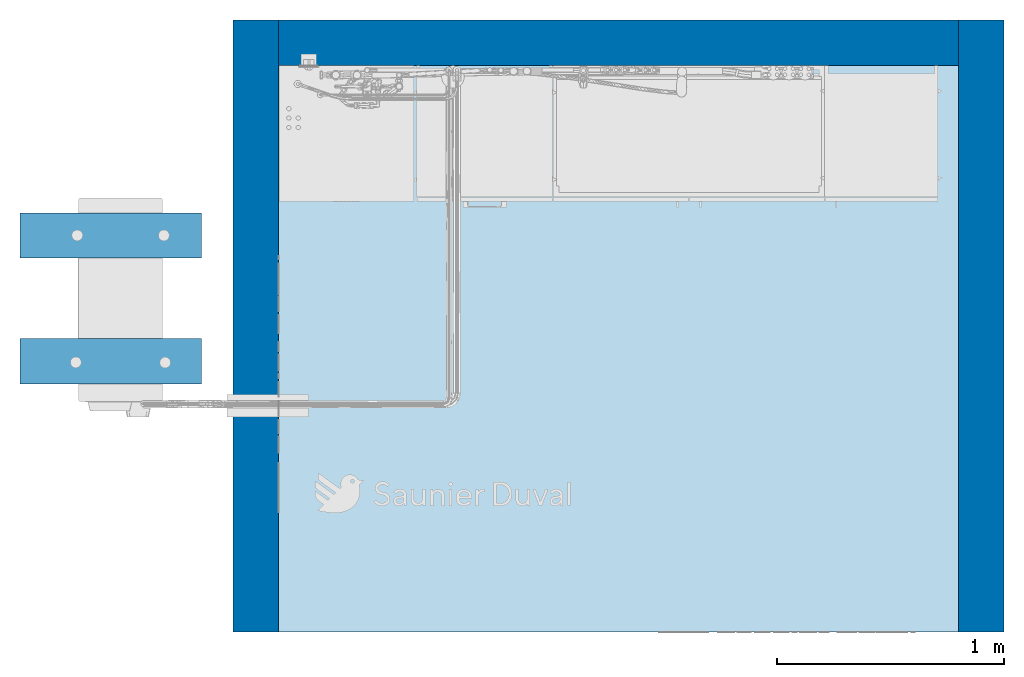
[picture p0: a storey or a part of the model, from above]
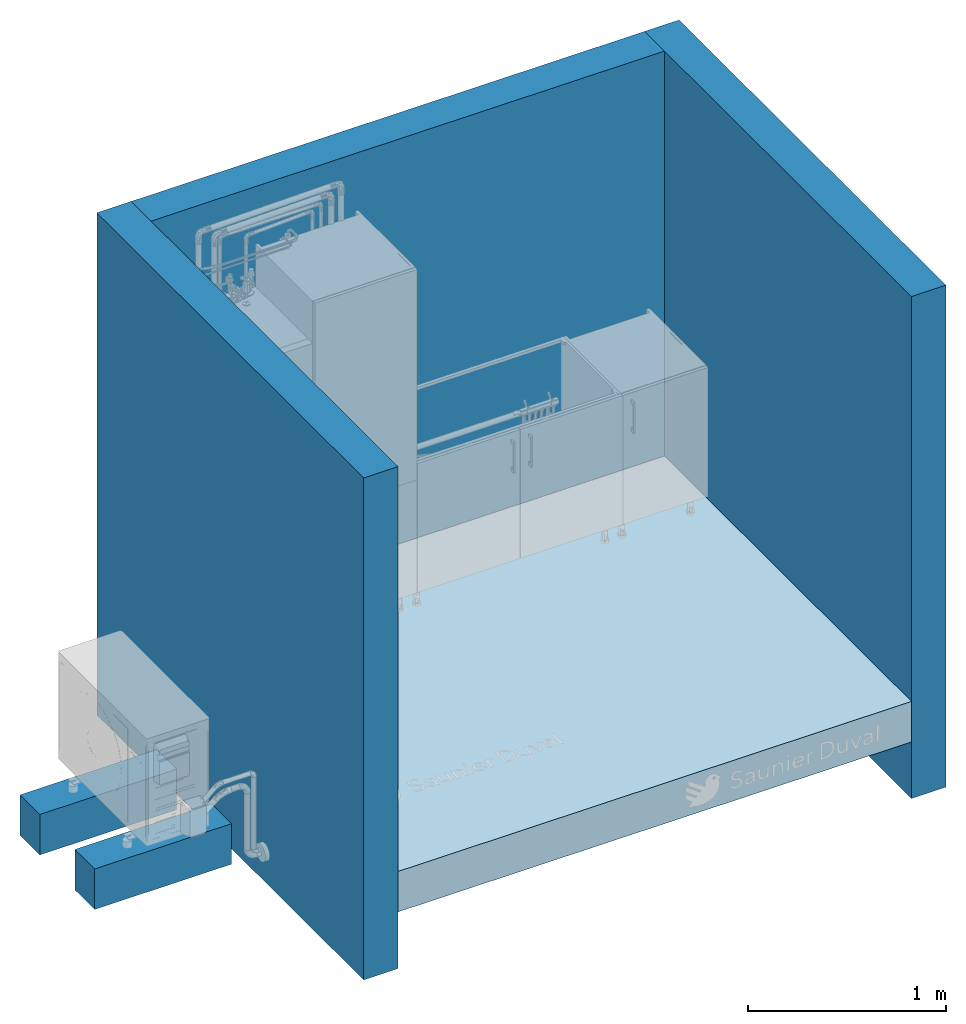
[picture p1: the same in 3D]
Properties of the parts of a building model (IFC2X3)

# File
Description: ViewDefinition [CoordinationView_V2.0], RevitIdentifiers [VersionGUID: d87a4e5c-1366-4f79-aa34-87cf10b37c27, NumberOfSaves: 158], CoordinateReference [CoordinateBase: Coordonnées partagées]
File name: 0001
Time: 2024-07-11T15:00:22+01:00
Written by: ODA SDAI 24.6
Made in: Autodesk Revit 24.2.0.63 (FRA) - IFC 24.2.0.63

# IfcProject, 0001
LongName: Salle de formation PAC SD; Phase: Etat du projet

# IfcSite, Default
RefLatitude: 48, 52, 0, 117187; RefLongitude: 2, 19, 59, 880409; RefElevation: 0 m

# IfcBuilding
Pset_BuildingCommon - NumberOfStoreys: 1

# IfcBuildingStorey: Niveau:Ligne du Niveau (2)
Name | LongName | Elevation (m)
Niveau 0 | Niveau 0 | -1.94916e-14
Niveau 1 | Niveau 1 | 2.5

# IfcBuildingElementProxy: Legrand Boite encastrement batibox 1 poste1:1 poste, Legrand Boite encastrement batibox 1 poste1:1 poste:1152296
In: Niveau 0
Type - Material: Plastique orange
Type - Pset_ManufacturerTypeInformation - Manufacturer: Legrand
Pset_BuildingElementProxyCommon - Reference: 1 poste; sets with these values: 2

# IfcBuildingElementProxy: Legrand Sorties de câbles:Prise courant, Legrand Sorties de câbles:Prise courant:1152295
In: Niveau 0
Type - Material: Plastique, blanc opaque, Plastique, noir opaque
Type - Pset_ManufacturerTypeInformation - Manufacturer: Legrand
Pset_BuildingElementProxyCommon - Reference: Prise courant; sets with these values: 2

# IfcBuildingElementProxy: Legrand plaque2:1 poste, Legrand plaque2:1 poste:1152297
In: Niveau 0
Type - Material: Plastique, blanc opaque
Type - Pset_ManufacturerTypeInformation - Manufacturer: Legrand
Pset_BuildingElementProxyCommon - Reference: 1 poste; sets with these values: 2

# IfcBuildingElementProxy: Legrand support universel-20181:1 poste, Legrand support universel-20181:1 poste:1152298
In: Niveau 0
Type - Material: Plastique, noir opaque
Type - Pset_ManufacturerTypeInformation - Manufacturer: Legrand
Pset_BuildingElementProxyCommon - Reference: 1 poste; sets with these values: 2

# IfcBuildingElementProxy: Logo_Geometry_SD_3Dx10-:Mur_horizontal (2)
In: Niveau 0
Type - Material: Color RGB 251-026-031, Color RGB 10-10-10
Pset_BuildingElementProxyCommon - Reference: Mur_horizontal; sets with these values: 2
Name (Logo_Geometry_SD_3Dx10-:Mur_horizontal:...)
1152291
1152294

# IfcBuildingElementProxy: Logo_Geometry_SD_3Dx10-:Sol, Logo_Geometry_SD_3Dx10-:Sol:1152293
In: Niveau 0
Type - Material: Color RGB 251-026-031, Color RGB 10-10-10
Pset_BuildingElementProxyCommon - Reference: Sol; sets with these values: 2

# IfcBuildingElementProxy: Pied antivibratile ep 40:Pied antivibratile ep 40 (4)
In: Niveau 0
Type - Material: Valeur par défaut Nouveau Matériau
Pset_BuildingElementProxyCommon - Reference: Pied antivibratile ep 40; sets with these values: 2
Name (Pied antivibratile ep 40:Pied antivibratile ep 40:...)
1152043
1152044
1152045
1152046

# IfcBuildingElementProxy: R580F:R580 3/4" x 1/2", R580F:R580 3/4" x 1/2":1152158
In: Niveau 0
Type - Material: Color RGB 169-131-7, Matériau du rendu 255-0-0
Material: <Unnamed>, Color RGB 169-131-7, Matériau du rendu 255-0-0; Group: Chauffage retour 2; Chauffage aller 1; Alimentation hydraulique 46; Alimentation hydraulique 45; Alimentation hydraulique 44; Alimentation hydraulique 43; Alimentation hydraulique 42; Alimentation hydraulique 41; Retour hydraulique 25; Retour hydraulique 24; Retour hydraulique 23; Retour hydraulique 22; Retour hydraulique 21; Retour hydraulique 20
Pset_BuildingElementProxyCommon - Reference: R580 3/4" x 1/2"; sets with these values: 2

# IfcCovering: Isolation des canalisations:Par défaut (24)
In: Niveau 0
Type - PredefinedType: INSULATION
Material: Matériau du rendu 255-255-255
Pset_CoveringCommon - Reference: Par défaut; sets with these values: 2
Name (Isolation des canalisations:Par défaut:...)
1152861
1152862
1152863
1152864
1152865
1152866
1152867
1152868
1152869
1152870
1152871
1152874
1152907
1152908
1152909
1152911
1152912
1152913
1152914
1152915
1152916
1152917
1152918
1219209

# IfcDistributionPort (264)
Description: Flow
Name | FlowDirection | Group
Port_530808_1 | SOURCEANDSINK | Alimentation hydraulique 3
Port_530808_2 | SOURCEANDSINK | Alimentation hydraulique 3
InPort_1152054_1 | SINK
InPort_1152054_2 | SINK
OutPort_1152054_3 | SOURCE | Sanitaire 20
Port_1152055_0 | SOURCEANDSINK | Sanitaire 21
Port_1152055_1 | SOURCEANDSINK | Sanitaire 21
InPort_1152065_4 | SINK | Retour hydraulique 10
OutPort_1152066_0 | SOURCE | Retour hydraulique 10
InPort_1152074_1 | SINK | Alimentation hydraulique 14
OutPort_1152065_5 | SOURCE | Alimentation hydraulique 14
Port_1152065_6 | SOURCEANDSINK
InPort_1152066_1 | SINK | Retour hydraulique 10
OutPort_1152068_1 | SOURCE | Retour hydraulique 10
InPort_1152068_2 | SINK | Retour hydraulique 10
OutPort_1152070_0 | SOURCE | Retour hydraulique 10
InPort_1152070_1 | SINK | Retour hydraulique 10
OutPort_1152220_1 | SOURCE | Retour hydraulique 10
InPort_1152236_1 | SINK | Alimentation hydraulique 14
OutPort_1152072_0 | SOURCE | Alimentation hydraulique 14
InPort_1152072_1 | SINK | Alimentation hydraulique 14
OutPort_1152076_1 | SOURCE | Alimentation hydraulique 14
InPort_1152076_2 | SINK | Alimentation hydraulique 14
OutPort_1152074_0 | SOURCE | Alimentation hydraulique 14
Port_1152086_0 | SOURCEANDSINK | Eau Froide Sanitaire 9
Port_1213014_1 | SOURCEANDSINK | Eau Froide Sanitaire 9
Port_1152086_1 | SOURCEANDSINK | Eau Froide Sanitaire 9
Port_1204610_1 | SOURCEANDSINK | Eau Froide Sanitaire 9
OutPort_1152098_0 | SOURCE | Chauffage retour 2
InPort_1152098_1 | SINK | Chauffage retour 2
OutPort_1218942_1 | SOURCE | Chauffage retour 2
OutPort_1152112_2 | SOURCE
InPort_1152112_5 | SINK | Eau Froide Sanitaire 9
OutPort_1152121_2 | SOURCE | Eau Froide Sanitaire 9
InPort_1152125_0 | SINK | Eau Froide Sanitaire 20
OutPort_1152112_6 | SOURCE | Eau Froide Sanitaire 20
InPort_1152123_0 | SINK | Eau Froide Sanitaire 19
OutPort_1152112_7 | SOURCE | Eau Froide Sanitaire 19
InPort_1152127_0 | SINK | Eau Froide Sanitaire 21
OutPort_1152112_8 | SOURCE | Eau Froide Sanitaire 21
InPort_1152119_0 | SINK | Eau Froide Sanitaire 9
OutPort_1205700_3 | SOURCE | Eau Froide Sanitaire 9
InPort_1152121_1 | SINK | Eau Froide Sanitaire 9
OutPort_1152119_1 | SOURCE | Eau Froide Sanitaire 9
OutPort_1152123_1 | SOURCE | Eau Froide Sanitaire 19
OutPort_1152125_1 | SOURCE | Eau Froide Sanitaire 20
OutPort_1152127_1 | SOURCE | Eau Froide Sanitaire 21
OutPort_1152129_2 | SOURCE
InPort_1152129_5 | SINK | Eau Chaude Sanitaire 9
OutPort_1152154_1 | SOURCE | Eau Chaude Sanitaire 9
OutPort_1152129_6 | SOURCE
InPort_1152136_0 | SINK | Eau Chaude Sanitaire 10
OutPort_1152129_7 | SOURCE | Eau Chaude Sanitaire 10
InPort_1152138_0 | SINK | Eau Chaude Sanitaire 11
OutPort_1152129_8 | SOURCE | Eau Chaude Sanitaire 11
OutPort_1152136_1 | SOURCE | Eau Chaude Sanitaire 10
OutPort_1152138_1 | SOURCE | Eau Chaude Sanitaire 11
InPort_1152144_1 | SINK | Eau Froide Sanitaire 9
OutPort_1152142_0 | SOURCE | Eau Froide Sanitaire 9
InPort_1152142_1 | SINK | Eau Froide Sanitaire 9
InPort_1152145_1 | SINK | Eau Froide Sanitaire 9
OutPort_1152144_2 | SOURCE | Eau Froide Sanitaire 9
InPort_1152147_1 | SINK | Eau Froide Sanitaire 9
OutPort_1152145_0 | SOURCE | Eau Froide Sanitaire 9
InPort_1205681_1 | SINK | Eau Froide Sanitaire 9
OutPort_1152147_2 | SOURCE | Eau Froide Sanitaire 9
InPort_1152154_2 | SINK | Eau Chaude Sanitaire 9
OutPort_1152152_0 | SOURCE | Eau Chaude Sanitaire 9
InPort_1152152_1 | SINK | Eau Chaude Sanitaire 9
OutPort_1152156_2 | SOURCE | Eau Chaude Sanitaire 9
InPort_1152156_1 | SINK | Eau Chaude Sanitaire 9
OutPort_1212866_0 | SOURCE | Eau Chaude Sanitaire 9
InPort_1152158_1 | SINK | Chauffage aller 1
OutPort_1217464_2 | SOURCE | Chauffage aller 1
InPort_1213780_1 | SINK | Chauffage retour 2
OutPort_1152158_2 | SOURCE | Chauffage retour 2
InPort_1152199_0 | SINK | Alimentation hydraulique 46
OutPort_1152158_3 | SOURCE | Alimentation hydraulique 46
InPort_1152197_0 | SINK | Alimentation hydraulique 45
OutPort_1152158_4 | SOURCE | Alimentation hydraulique 45
InPort_1152195_0 | SINK | Alimentation hydraulique 44
OutPort_1152158_5 | SOURCE | Alimentation hydraulique 44
InPort_1152193_0 | SINK | Alimentation hydraulique 43
OutPort_1152158_6 | SOURCE | Alimentation hydraulique 43
InPort_1152191_0 | SINK | Alimentation hydraulique 42
OutPort_1152158_7 | SOURCE | Alimentation hydraulique 42
InPort_1152189_0 | SINK | Alimentation hydraulique 41
OutPort_1152158_8 | SOURCE | Alimentation hydraulique 41
InPort_1152158_9 | SINK | Retour hydraulique 25
OutPort_1152187_0 | SOURCE | Retour hydraulique 25
InPort_1152158_10 | SINK | Retour hydraulique 24
OutPort_1152185_0 | SOURCE | Retour hydraulique 24
InPort_1152158_11 | SINK | Retour hydraulique 23
OutPort_1152183_0 | SOURCE | Retour hydraulique 23
InPort_1152158_12 | SINK | Retour hydraulique 22
OutPort_1152181_0 | SOURCE | Retour hydraulique 22
InPort_1152158_13 | SINK | Retour hydraulique 21
OutPort_1152179_0 | SOURCE | Retour hydraulique 21
InPort_1152158_14 | SINK | Retour hydraulique 20
OutPort_1152177_0 | SOURCE | Retour hydraulique 20
InPort_1218810_1 | SINK | Chauffage retour 2
OutPort_1152161_0 | SOURCE | Chauffage retour 2
InPort_1152161_1 | SINK | Chauffage retour 2
OutPort_1214416_2 | SOURCE | Chauffage retour 2
InPort_1152177_1 | SINK | Retour hydraulique 20
InPort_1152179_1 | SINK | Retour hydraulique 21
InPort_1152181_1 | SINK | Retour hydraulique 22
InPort_1152183_1 | SINK | Retour hydraulique 23
InPort_1152185_1 | SINK | Retour hydraulique 24
InPort_1152187_1 | SINK | Retour hydraulique 25
OutPort_1152189_1 | SOURCE | Alimentation hydraulique 41
OutPort_1152191_1 | SOURCE | Alimentation hydraulique 42
OutPort_1152193_1 | SOURCE | Alimentation hydraulique 43
OutPort_1152195_1 | SOURCE | Alimentation hydraulique 44
OutPort_1152197_1 | SOURCE | Alimentation hydraulique 45
OutPort_1152199_1 | SOURCE | Alimentation hydraulique 46
Port_1152201_0 | SOURCEANDSINK | Alimentation hydraulique 54
Port_1152201_1 | SOURCEANDSINK | Alimentation hydraulique 54
InPort_1152210_0 | SINK | Alimentation hydraulique 14
OutPort_1152836_2 | SOURCE | Alimentation hydraulique 14
InPort_1219448_1 | SINK | Alimentation hydraulique 14
OutPort_1152210_1 | SOURCE | Alimentation hydraulique 14
InPort_1152214_0 | SINK | Alimentation hydraulique 55
OutPort_1152216_2 | SOURCE | Alimentation hydraulique 55
InPort_1152224_2 | SINK | Alimentation hydraulique 55
OutPort_1152214_1 | SOURCE | Alimentation hydraulique 55
InPort_1152216_1 | SINK | Alimentation hydraulique 55
OutPort_1219199_0 | SOURCE | Alimentation hydraulique 55
InPort_1152220_2 | SINK | Retour hydraulique 10
OutPort_1152218_0 | SOURCE | Retour hydraulique 10
InPort_1152218_1 | SINK | Alimentation hydraulique 55
OutPort_1152226_1 | SOURCE | Alimentation hydraulique 55
InPort_1152222_0 | SINK | Alimentation hydraulique 55
OutPort_1152224_1 | SOURCE | Alimentation hydraulique 55
InPort_1152226_2 | SINK | Alimentation hydraulique 55
OutPort_1152222_1 | SOURCE | Alimentation hydraulique 55
InPort_1152836_1 | SINK | Alimentation hydraulique 14
OutPort_1152228_0 | SOURCE | Alimentation hydraulique 14
InPort_1152228_1 | SINK | Alimentation hydraulique 14
OutPort_1152240_2 | SOURCE | Alimentation hydraulique 14
InPort_1152232_0 | SINK | Alimentation hydraulique 14
OutPort_1152238_2 | SOURCE | Alimentation hydraulique 14
InPort_1152240_1 | SINK | Alimentation hydraulique 14
OutPort_1152232_1 | SOURCE | Alimentation hydraulique 14
InPort_1152234_0 | SINK | Alimentation hydraulique 14
OutPort_1152236_2 | SOURCE | Alimentation hydraulique 14
InPort_1152238_1 | SINK | Alimentation hydraulique 14
OutPort_1152234_1 | SOURCE | Alimentation hydraulique 14
Port_1152242_0 | SOURCEANDSINK | Alimentation hydraulique 57
Port_1152242_1 | SOURCEANDSINK | Alimentation hydraulique 57
Port_1152244_0 | SOURCEANDSINK | Alimentation hydraulique 58
Port_1152244_1 | SOURCEANDSINK | Alimentation hydraulique 58
Port_1152246_0 | SOURCEANDSINK | Alimentation hydraulique 59
Port_1152246_1 | SOURCEANDSINK | Alimentation hydraulique 59
Port_1152250_0 | SOURCEANDSINK | Alimentation hydraulique 61
Port_1152250_1 | SOURCEANDSINK | Alimentation hydraulique 61
Port_1152252_0 | SOURCEANDSINK | Alimentation hydraulique 62
Port_1152252_1 | SOURCEANDSINK | Alimentation hydraulique 62
Port_1152254_0 | SOURCEANDSINK | Alimentation hydraulique 63
Port_1152254_1 | SOURCEANDSINK | Alimentation hydraulique 63
Port_1152256_0 | SOURCEANDSINK | Alimentation hydraulique 64
Port_1152256_1 | SOURCEANDSINK | Alimentation hydraulique 64
Port_1152258_0 | SOURCEANDSINK | Alimentation hydraulique 65
Port_1152258_1 | SOURCEANDSINK | Alimentation hydraulique 65
Port_1152260_0 | SOURCEANDSINK | Alimentation hydraulique 66
Port_1152260_1 | SOURCEANDSINK | Alimentation hydraulique 66
InPort_1152288_10 | SINK
OutPort_1152288_11 | SOURCE
OutPort_1152288_16 | SOURCE
InPort_1385587_1 | SINK | Chauffage aller 1
OutPort_1152288_17 | SOURCE | Chauffage aller 1
InPort_1152288_18 | SINK | Chauffage retour 2
OutPort_1152288_19 | SOURCE
InPort_1152288_20 | SINK
OutPort_1152288_21 | SOURCE
InPort_1152288_22 | SINK
InPort_1152288_23 | SINK
OutPort_1152288_24 | SOURCE
OutPort_1152288_25 | SOURCE
Port_1152288_26 | SOURCEANDSINK
InPort_1219095_1 | SINK | Alimentation hydraulique 55
OutPort_1152583_0 | SOURCE | Alimentation hydraulique 55
InPort_1152583_1 | SINK | Alimentation hydraulique 55
OutPort_1152782_0 | SOURCE | Sanitaire 23
InPort_1152782_1 | SINK | Sanitaire 23
OutPort_1219401_1 | SOURCE | Sanitaire 23
Port_1204610_2 | SOURCEANDSINK | Eau Froide Sanitaire 9
Port_1205701_0 | SOURCEANDSINK | Eau Froide Sanitaire 9
InPort_1205700_2 | SINK | Eau Froide Sanitaire 9
OutPort_1205681_0 | SOURCE | Eau Froide Sanitaire 9
Port_1205700_1 | SOURCEANDSINK | Eau Froide Sanitaire 9
Port_1205701_1 | SOURCEANDSINK | Eau Froide Sanitaire 9
Port_1212275_0 | SOURCEANDSINK | Eau Froide Sanitaire 9
Port_1212275_1 | SOURCEANDSINK | Eau Froide Sanitaire 9
Port_1213012_1 | SOURCEANDSINK | Eau Froide Sanitaire 9
Port_1212283_0 | SOURCEANDSINK | Eau Froide Sanitaire 9
Port_1213012_2 | SOURCEANDSINK | Eau Froide Sanitaire 9
Port_1212283_1 | SOURCEANDSINK | Eau Froide Sanitaire 9
Port_1213014_2 | SOURCEANDSINK | Eau Froide Sanitaire 9
InPort_1212848_0 | SINK | Eau Chaude Sanitaire 9
InPort_1212864_1 | SINK | Eau Chaude Sanitaire 9
OutPort_1212848_1 | SOURCE | Eau Chaude Sanitaire 9
InPort_1212858_0 | SINK | Eau Chaude Sanitaire 9
OutPort_1212864_2 | SOURCE | Eau Chaude Sanitaire 9
InPort_1212876_1 | SINK | Eau Chaude Sanitaire 9
OutPort_1212858_1 | SOURCE | Eau Chaude Sanitaire 9
InPort_1212866_1 | SINK | Eau Chaude Sanitaire 9
OutPort_1212876_2 | SOURCE | Eau Chaude Sanitaire 9
InPort_1213375_0 | SINK | Chauffage aller 1
OutPort_1217659_1 | SOURCE | Chauffage aller 1
InPort_1217464_1 | SINK | Chauffage aller 1
OutPort_1213375_1 | SOURCE | Chauffage aller 1
InPort_1213766_0 | SINK | Chauffage retour 2
OutPort_1213780_2 | SOURCE | Chauffage retour 2
InPort_1213832_2 | SINK | Chauffage retour 2
OutPort_1213766_1 | SOURCE | Chauffage retour 2
InPort_1213782_0 | SINK | Chauffage retour 2
OutPort_1213832_1 | SOURCE | Chauffage retour 2
InPort_1214416_1 | SINK | Chauffage retour 2
OutPort_1213782_1 | SOURCE | Chauffage retour 2
InPort_1217659_2 | SINK | Chauffage aller 1
OutPort_1217651_0 | SOURCE | Chauffage aller 1
InPort_1217651_1 | SINK | Chauffage aller 1
OutPort_1218773_1 | SOURCE | Chauffage aller 1
InPort_1218218_0 | SINK | Chauffage aller 1
OutPort_1218771_2 | SOURCE | Chauffage aller 1
InPort_1218773_2 | SINK | Chauffage aller 1
OutPort_1218218_1 | SOURCE | Chauffage aller 1
InPort_1218771_1 | SINK | Chauffage aller 1
OutPort_1385587_0 | SOURCE | Chauffage aller 1
InPort_1218802_0 | SINK | Chauffage retour 2
OutPort_1218810_2 | SOURCE | Chauffage retour 2
InPort_1218940_1 | SINK | Chauffage retour 2
OutPort_1218802_1 | SOURCE | Chauffage retour 2
InPort_1218813_0 | SINK | Chauffage retour 2
OutPort_1218940_2 | SOURCE | Chauffage retour 2
InPort_1218942_2 | SINK | Chauffage retour 2
OutPort_1218813_1 | SOURCE | Chauffage retour 2
InPort_1219081_0 | SINK | Alimentation hydraulique 55
OutPort_1219095_2 | SOURCE | Alimentation hydraulique 55
InPort_1219197_1 | SINK | Alimentation hydraulique 55
OutPort_1219081_1 | SOURCE | Alimentation hydraulique 55
InPort_1219187_0 | SINK | Alimentation hydraulique 55
OutPort_1219197_2 | SOURCE | Alimentation hydraulique 55
InPort_1219210_1 | SINK | Alimentation hydraulique 55
OutPort_1219187_1 | SOURCE | Alimentation hydraulique 55
InPort_1219199_1 | SINK | Alimentation hydraulique 55
OutPort_1219210_2 | SOURCE | Alimentation hydraulique 55
InPort_1219401_2 | SINK | Sanitaire 23
OutPort_1219417_0 | SOURCE | Sanitaire 23
InPort_1219417_1 | SINK | Retour hydraulique 26
OutPort_1219434_1 | SOURCE | Retour hydraulique 26
InPort_1219434_2 | SINK | Retour hydraulique 26
OutPort_1219425_0 | SOURCE | Retour hydraulique 26
InPort_1219425_1 | SINK | Retour hydraulique 26
OutPort_1219452_1 | SOURCE | Retour hydraulique 26
InPort_1219438_0 | SINK | Retour hydraulique 26
OutPort_1219448_2 | SOURCE | Retour hydraulique 26
InPort_1219452_2 | SINK | Retour hydraulique 26
OutPort_1219438_1 | SOURCE | Retour hydraulique 26
Port_1286353_0 | SOURCEANDSINK | Alimentation hydraulique 47
Port_1286353_1 | SOURCEANDSINK | Alimentation hydraulique 47
Port_1385736_0 | SOURCEANDSINK | Sanitaire 22
Port_1385736_1 | SOURCEANDSINK | Sanitaire 22

# IfcFlowController: HC_Manifold_MEPcontent_Valsir_Pexal BRASS_3 Way Cold Water_INT-EN:1/2'' x 3/4'', HC_Manifold_MEPcontent_Valsir_Pexal BRASS_3 Way Cold Water_INT-EN:1/2'' x 3/4'':1152112
In: Niveau 0
Type - Material: Color RGB 202-154-058
Type - Pset_ElementShading - Color: Color RGB 202-154-058
Type - Pset_ManufacturerTypeInformation - Manufacturer: Valsir S.p.A.
Classification: SfB]53 (Default Classification); Group: Eau Froide Sanitaire 9; Eau Froide Sanitaire 20; Eau Froide Sanitaire 19; Eau Froide Sanitaire 21
Pset_DistributionFlowElementCommon - Reference: 1/2'' x 3/4''; sets with these values: 2

# IfcFlowController: HC_Manifold_MEPcontent_Valsir_Pexal BRASS_3 Way Hot Water_INT-EN:1/2'' x 3/4'', HC_Manifold_MEPcontent_Valsir_Pexal BRASS_3 Way Hot Water_INT-EN:1/2'' x 3/4'':1152129
In: Niveau 0
Type - Material: Color RGB 202-154-058
Type - Pset_ElementShading - Color: Color RGB 202-154-058
Type - Pset_ManufacturerTypeInformation - Manufacturer: Valsir S.p.A.
Classification: SfB]53 (Default Classification); Group: Eau Chaude Sanitaire 9; Eau Chaude Sanitaire 10; Eau Chaude Sanitaire 11
Pset_DistributionFlowElementCommon - Reference: 1/2'' x 3/4''; sets with these values: 2

# IfcFlowController: M_Valve_Ball_MEPcontent_Caleffi_327 DN20:3/4'', M_Valve_Ball_MEPcontent_Caleffi_327 DN20:3/4'':1152144
In: Niveau 0
Type - PredefinedType: REGULATING; Material: Color RGB 187-001-001, Color RGB 202-154-058, Color RGB 045-045-045
Type - Pset_DuctConnection - ConnectionType: Gas ISO 228/1
Type - Pset_ManufacturerTypeInformation - Manufacturer: Caleffi Italy
Type - Pset_PipeConnection - ConnectionType: Gas ISO 228/1
Material: Color RGB 045-045-045, Color RGB 202-154-058, Color RGB 187-001-001; Group: Eau Froide Sanitaire 9
Pset_DistributionFlowElementCommon - Reference: 3/4''; sets with these values: 2

# IfcFlowController: Plumbing_Valves_Caleffi_Pressure_ Reducing_ Valve-533HA-DN15_DN20:533340HA, Plumbing_Valves_Caleffi_Pressure_ Reducing_ Valve-533HA-DN15_DN20:533340HA:1152147
In: Niveau 0
Type - Material: Metal - Caleffi - Brass, Technopolymer - Caleffi - Black, Technopolymer - Caleffi - Grey
Type - Pset_DuctConnection - ConnectionType: NPT
Type - Pset_ManufacturerTypeInformation - Manufacturer: Caleffi North America, Inc.
Type - Pset_PipeConnection - ConnectionType: NPT
Classification: D3040 Uniformat (Uniformat); Group: Eau Froide Sanitaire 9
Pset_DistributionFlowElementCommon - Reference: 533340HA; sets with these values: 2

# IfcFlowController: Raccordement sur Siphon avec syphon:Raccordement sur Siphon avec syphon, Raccordement sur Siphon avec syphon:Raccordement sur Siphon avec syphon:1152054
In: Niveau 0
Type - Material: <Unnamed>
Type - Pset_ManufacturerTypeInformation - Manufacturer: GIRPI
Pset_DistributionFlowElementCommon - Reference: Raccordement sur Siphon avec syphon; sets with these values: 2
Group: Sanitaire 20

# IfcFlowFitting: COMAP - MULTISKIN - Coude Cintre:Standard (2)
In: Niveau 0
Type - Material: Comap, <Unnamed>
Pset_DistributionFlowElementCommon - Reference: Standard; sets with these values: 2
Group: Chauffage retour 2
Name (COMAP - MULTISKIN - Coude Cintre:Standard:...)
1213832
1214416

# IfcFlowFitting: COMAP - SKINPRESS ppsu - Coude_45_90_9041W_9090W:Coude_45_90_9041W_9090W (12)
In: Niveau 0
Type - Material: PPSU, Bague blanche VisuControl, Inox
Type - Pset_ManufacturerTypeInformation - Manufacturer: COMAP
Pset_DistributionFlowElementCommon - Reference: Coude_45_90_9041W_9090W; sets with these values: 2
Name (COMAP - SKINPRESS ppsu - Coude_45_90_9041W_9090W:Coude_45_90_9041W_9090W:...) | Group | Material
1152156 | Eau Chaude Sanitaire 9
1204610 | Eau Froide Sanitaire 9 | Bague blanche VisuControl, Inox, PPSU
1212864 | Eau Chaude Sanitaire 9 | Bague blanche VisuControl, Inox, PPSU
1212876 | Eau Chaude Sanitaire 9 | Bague blanche VisuControl, Inox, PPSU
1213012 | Eau Froide Sanitaire 9 | Bague blanche VisuControl, Inox, PPSU
1213014 | Eau Froide Sanitaire 9 | Bague blanche VisuControl, Inox, PPSU
1217659 | Chauffage aller 1
1218771 | Chauffage aller 1 | Bague blanche VisuControl, Inox, PPSU
1218773 | Chauffage aller 1 | Bague blanche VisuControl, Inox, PPSU
1218810 | Chauffage retour 2 | Bague blanche VisuControl, Inox, PPSU
1218940 | Chauffage retour 2 | Bague blanche VisuControl, Inox, PPSU
1218942 | Chauffage retour 2 | Bague blanche VisuControl, Inox, PPSU

# IfcFlowFitting: COMAP - SKINPRESS ppsu - Manchon_Réduit_9240W:Manchon_Réduit_9240W (4)
In: Niveau 0
Type - Material: Bague blanche VisuControl, Inox, PPSU
Type - Pset_ManufacturerTypeInformation - Manufacturer: COMAP
Pset_DistributionFlowElementCommon - Reference: Manchon_Réduit_9240W; sets with these values: 2
Name (COMAP - SKINPRESS ppsu - Manchon_Réduit_9240W:Manchon_Réduit_9240W:...) | Group
1152121 | Eau Froide Sanitaire 9
1152154 | Eau Chaude Sanitaire 9
1213780 | Chauffage retour 2
1217464 | Chauffage aller 1

# IfcFlowFitting: COMAP - SKINPRESS ppsu - Té_égal_réduit_9130W_9130RW:Standard, COMAP - SKINPRESS ppsu - Té_égal_réduit_9130W_9130RW:Standard:1205700
In: Niveau 0
Type - Material: Bague blanche VisuControl, Inox, PPSU
Type - Pset_ManufacturerTypeInformation - Manufacturer: COMAP
Pset_DistributionFlowElementCommon - Reference: Standard; sets with these values: 2
Group: Eau Froide Sanitaire 9

# IfcFlowFitting: Coude - tube frigo:Standard (18)
In: Niveau 0
Type - Material: Cuivre
Pset_DistributionFlowElementCommon - Reference: Standard; sets with these values: 2
Name (Coude - tube frigo:Standard:...) | Group
530808 | Alimentation hydraulique 3
1152068 | Retour hydraulique 10
1152076 | Alimentation hydraulique 14
1152216 | Alimentation hydraulique 55
1152220 | Retour hydraulique 10
1152224 | Alimentation hydraulique 55
1152226 | Alimentation hydraulique 55
1152236 | Alimentation hydraulique 14
1152238 | Alimentation hydraulique 14
1152240 | Alimentation hydraulique 14
1152836 | Alimentation hydraulique 14
1219095 | Alimentation hydraulique 55
1219197 | Alimentation hydraulique 55
1219210 | Alimentation hydraulique 55
1219401 | Sanitaire 23
1219434 | Retour hydraulique 26
1219448 | Alimentation hydraulique 14; Retour hydraulique 26
1219452 | Retour hydraulique 26

# IfcFlowFitting: SA_Connection Piece_MEPcontent_Valsir_Pexal BRASS_Kit with Nut_Shared:14 mm x 2 mm-1/2'' (6)
In: Niveau 0
Type - Material: Color RGB 202-154-058
Type - Pset_ElementShading - Color: Color RGB 202-154-058
Type - Pset_FlowFittingDuctFitting - Color: Color RGB 202-154-058
Type - Pset_FlowFittingPipeFitting - Color: Color RGB 202-154-058
Type - Pset_ManufacturerTypeInformation - Manufacturer: Valsir S.p.A.
Classification: SfB]53 (Default Classification)
Pset_DistributionFlowElementCommon - Reference: 14 mm x 2 mm-1/2''; sets with these values: 2
Name (SA_Connection Piece_MEPcontent_Valsir_Pexal BRASS_Kit with Nut_Shared:14 mm x 2 mm-1/2'':...)
1152113
1152114
1152115
1152130
1152131
1152132

# IfcFlowMovingDevice: HC_Heat Pump_GM_Saunier Duval_GeniaSet TEK_IS_kit complet+2C:HA 10-7_2 STB, HC_Heat Pump_GM_Saunier Duval_GeniaSet TEK_IS_kit complet+2C:HA 10-7_2 STB:1152288
In: Niveau 0
Type - Material: Color RGB 121-121-121, Color RGB 244-244-244, Color RGB 116-051-029, Color RGB 040-040-040, Color RGB 251-026-031, Color RGB 191-153-066
Type - Pset_ManufacturerTypeInformation - Manufacturer: Saunier Duval
Material: Color RGB 191-153-066, Color RGB 040-040-040, Color RGB 000-000-255, Color RGB 116-051-029, <Unnamed>, Color RGB 120-120-120, Color RGB 251-026-031, Color RGB 121-121-121, Color RGB 244-244-244; Group: Chauffage retour 2; Chauffage aller 1
Pset_DistributionFlowElementCommon - Reference: HA 10-7_2 STB; sets with these values: 2

# IfcFlowMovingDevice: HC_Heat Pump_MEPcontent_Saunier Duval_GeniaAir TEK_HA 4-6_FR-FR:HA 4-7_2 OS 230V B3, HC_Heat Pump_MEPcontent_Saunier Duval_GeniaAir TEK_HA 4-6_FR-FR:HA 4-7_2 OS 230V B3:1152065
In: Niveau 0
Type - Material: Color RGB 040-040-040, Color RGB 251-026-031, Color RGB 235-235-235, Color RGB 190-190-190, Color RGB 174-174-174
Type - Pset_ManufacturerTypeInformation - Manufacturer: Saunier Duval
Pset_DistributionFlowElementCommon - Reference: HA 4-7_2 OS 230V B3; sets with these values: 2
Group: Retour hydraulique 10; Alimentation hydraulique 14

# IfcFlowSegment: Canalisation souple arrondie:Souple - Arrondie, Canalisation souple arrondie:Souple - Arrondie:1385736
In: Niveau 0
Type - PredefinedType: FLEXIBLESEGMENT
Pset_DistributionFlowElementCommon - Reference: Souple - Arrondie; sets with these values: 2
Group: Sanitaire 22

# IfcFlowSegment: Canalisation:COMAP MULTISKIN - SKINPRESS PPSU (27)
In: Niveau 0
Type - Pset_ManufacturerTypeInformation - Manufacturer: COMAP
Pset_DistributionFlowElementCommon - Reference: COMAP MULTISKIN - SKINPRESS PPSU; sets with these values: 2
Pset_FlowSegmentDuctSegment - sets with these values: 2
Name (Canalisation:COMAP MULTISKIN - SKINPRESS PPSU:...) | Length (m) | Group
1152086 | 1.91004 | Eau Froide Sanitaire 9
1152098 | 0.258338 | Chauffage retour 2
1152119 | 0.0552079 | Eau Froide Sanitaire 9
1152123 | 0.6016 | Eau Froide Sanitaire 19
1152125 | 0.6016 | Eau Froide Sanitaire 20
1152127 | 0.6 | Eau Froide Sanitaire 21
1152136 | 0.6516 | Eau Chaude Sanitaire 10
1152138 | 0.65 | Eau Chaude Sanitaire 11
1152142 | 0.353 | Eau Froide Sanitaire 9
1152145 | 0.02975 | Eau Froide Sanitaire 9
1152152 | 0.548497 | Eau Chaude Sanitaire 9
1152161 | 0.883505 | Chauffage retour 2
1205681 | 0.05325 | Eau Froide Sanitaire 9
1205701 | 0.3725 | Eau Froide Sanitaire 9
1212275 | 0.213533 | Eau Froide Sanitaire 9
1212283 | 0.360626 | Eau Froide Sanitaire 9
1212848 | 0.296588 | Eau Chaude Sanitaire 9
1212858 | 0.55 | Eau Chaude Sanitaire 9
1212866 | 1.8905 | Eau Chaude Sanitaire 9
1213375 | 0.994192 | Chauffage aller 1
1213766 | 0.0424575 | Chauffage retour 2
1213782 | 0.0108929 | Chauffage retour 2
1217651 | 1.71136 | Chauffage aller 1
1218218 | 0.767199 | Chauffage aller 1
1218802 | 1.77678 | Chauffage retour 2
1218813 | 0.615715 | Chauffage retour 2
1385587 | 0.30955 | Chauffage aller 1

# IfcFlowSegment: Canalisation:Cuivre Frigo (19)
In: Niveau 0
Pset_DistributionFlowElementCommon - Reference: Cuivre Frigo; sets with these values: 2
Pset_FlowSegmentDuctSegment - sets with these values: 2
Name (Canalisation:Cuivre Frigo:...) | Length (m) | Group
1152066 | 0.1455 | Retour hydraulique 10
1152070 | 0.159449 | Retour hydraulique 10
1152072 | 0.0496756 | Alimentation hydraulique 14
1152074 | 0.137924 | Alimentation hydraulique 14
1152210 | 2.52154 | Alimentation hydraulique 14
1152214 | 1.42302 | Alimentation hydraulique 55
1152218 | 0.445144 | Retour hydraulique 10; Alimentation hydraulique 55
1152222 | 0.965544 | Alimentation hydraulique 55
1152228 | 1.37562 | Alimentation hydraulique 14
1152232 | 0.988947 | Alimentation hydraulique 14
1152234 | 0.352103 | Alimentation hydraulique 14
1152583 | 0.207989 | Alimentation hydraulique 55
1152782 | 0.210838 | Sanitaire 23
1219081 | 0.519925 | Alimentation hydraulique 55
1219187 | 0.06055 | Alimentation hydraulique 55
1219199 | 2.51389 | Alimentation hydraulique 55
1219417 | 0.103016 | Sanitaire 23; Retour hydraulique 26
1219425 | 0.412738 | Retour hydraulique 26
1219438 | 0.0292506 | Retour hydraulique 26

# IfcFlowSegment: Canalisation:PER Bleu (6)
In: Niveau 0
Pset_DistributionFlowElementCommon - Reference: PER Bleu; sets with these values: 2
Pset_FlowSegmentDuctSegment - sets with these values: 2
Name (Canalisation:PER Bleu:...) | Length (m) | Group
1152177 | 0.596144 | Retour hydraulique 20
1152179 | 0.594808 | Retour hydraulique 21
1152181 | 0.594808 | Retour hydraulique 22
1152183 | 0.596144 | Retour hydraulique 23
1152185 | 0.596144 | Retour hydraulique 24
1152187 | 0.596144 | Retour hydraulique 25

# IfcFlowSegment: Canalisation:PER Rouge (6)
In: Niveau 0
Pset_DistributionFlowElementCommon - Reference: PER Rouge; sets with these values: 2
Pset_FlowSegmentDuctSegment - sets with these values: 2
Name (Canalisation:PER Rouge:...) | Length (m) | Group
1152189 | 0.576842 | Alimentation hydraulique 41
1152191 | 0.576842 | Alimentation hydraulique 42
1152193 | 0.595414 | Alimentation hydraulique 43
1152195 | 0.595414 | Alimentation hydraulique 44
1152197 | 0.595414 | Alimentation hydraulique 45
1152199 | 0.595414 | Alimentation hydraulique 46

# IfcFlowSegment: Canalisation:PVC - NF (12)
In: Niveau 0
Pset_DistributionFlowElementCommon - Reference: PVC - NF; sets with these values: 2
Pset_FlowSegmentDuctSegment - sets with these values: 2
Name (Canalisation:PVC - NF:...) | Length (m) | Group
1152055 | 0.35 | Sanitaire 21
1152201 | 0.365 | Alimentation hydraulique 54 | Material: Porte - Panneau
1152242 | 0.368153 | Alimentation hydraulique 57
1152244 | 0.368153 | Alimentation hydraulique 58
1152246 | 0.368153 | Alimentation hydraulique 59
1152250 | 0.368153 | Alimentation hydraulique 61
1152252 | 0.368153 | Alimentation hydraulique 62
1152254 | 0.368153 | Alimentation hydraulique 63
1152256 | 0.368153 | Alimentation hydraulique 64
1152258 | 0.368153 | Alimentation hydraulique 65
1152260 | 0.36 | Alimentation hydraulique 66
1286353 | 0.368153 | Alimentation hydraulique 47

# IfcFurnishingElement: Kitchen_Cabinets_FINSA_Pro-Base-Sink-unit-1200-blanc:Opening Type - (Two hinged doors) Height - (800 mm), Kitchen_Cabinets_FINSA_Pro-Base-Sink-unit-1200-blanc:Opening Type - (Two hinged doors) Height - (800 mm):1380557
In: Niveau 0
Type - Material: Blanco Medio, Black, Aluminio
Pset_QuantityTakeOff - Reference: Opening Type - (Two hinged doors) Height - (800 mm)

# IfcFurnishingElement: Kitchen_Cabinets_FINSA_Pro-Base-unit-500_blanc:Opening Type - (One right hinged door) Height - (800 mm), Kitchen_Cabinets_FINSA_Pro-Base-unit-500_blanc:Opening Type - (One right hinged door) Height - (800 mm):1383563
In: Niveau 0
Type - Material: Blanco Medio, Brown, Aluminio, Black
Pset_QuantityTakeOff - Reference: Opening Type - (One right hinged door) Height - (800 mm)

# IfcFurnishingElement: Kitchen_Cabinets_FINSA_Pro-Oven-Larder-unit-rd4d_Blanc:Height - (2000 mm), Kitchen_Cabinets_FINSA_Pro-Oven-Larder-unit-rd4d_Blanc:Height - (2000 mm):1376747
In: Niveau 0
Type - Material: Blanco Medio, Matériau du rendu 255-255-255, Aluminio, Black
Pset_QuantityTakeOff - Reference: Height - (2000 mm)

# IfcOpeningElement: Opening, Sol:Dalle en béton - 250 mm:634
In: Niveau 0
Pset_OpeningElementCommon - Reference: Dalle en béton - 250 mm; sets with these values: 2

# IfcOpeningElement: Recess, Mur de base:Générique - Ext. 200 mm:1152204
In: Niveau 0
Pset_OpeningElementCommon - Reference: 1 poste; sets with these values: 2

# IfcSlab: Sol:Dalle en béton - 250 mm (3)
In: Niveau 0
Type - PredefinedType: FLOOR; Material: Maçonnerie - Béton 0.25 m
Type - Pset_SlabCommon - IsExternal: no
Pset_QuantityTakeOff - Reference: Dalle en béton - 250 mm; sets with these values: 2
Pset_SlabCommon - Reference: Dalle en béton - 250 mm; PitchAngle: 0 deg
Name (Sol:Dalle en béton - 250 mm:...) | LoadBearing
1152009 | yes
1152049 | no
1152059 | no

# IfcWallStandardCase: Mur de base:Générique - Ext. 200 mm (3)
In: Niveau 0
Type - PredefinedType: STANDARD; Material: Mur par défaut 0.2 m, Color RGB 255-255-255 0.001 m
Type - Pset_WallCommon - IsExternal: yes
Pset_QuantityTakeOff - Reference: Générique - Ext. 200 mm; sets with these values: 2
Pset_WallCommon - Reference: Générique - Ext. 200 mm; ExtendToStructure: no; LoadBearing: yes
Name (Mur de base:Générique - Ext. 200 mm:...)
1152005
1152006
1152204
